(* Logix 5000 project; controller MVI56E_DNPNET 1756-L63 rev 16.7; software revision 16.04; part 2 of 2 *)
(* tags used below, declared in another part *)
   Connection_Output : INT[248];   // Output parameters.
   MJFAULTS : DINT[12];
(* AOI56EDNPNET, continued *)

ROUTINE Prescan   (* ladder *)
// Prescan
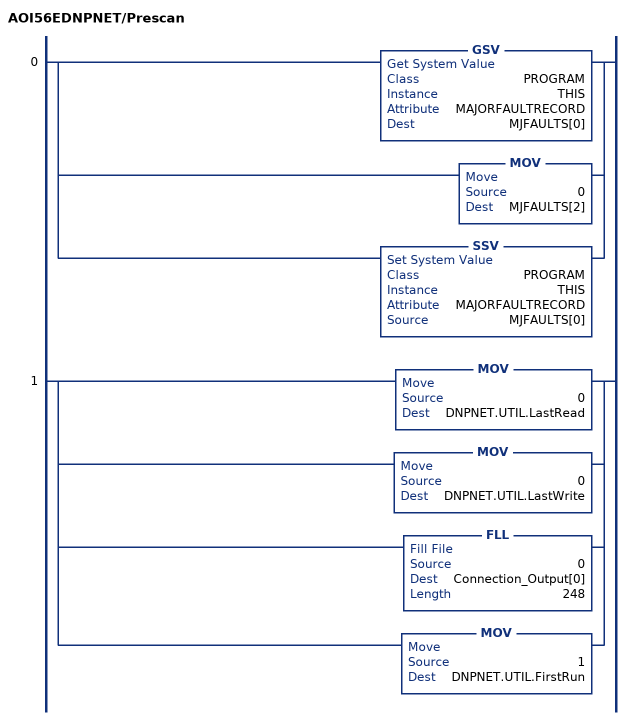
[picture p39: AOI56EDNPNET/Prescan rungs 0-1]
   0: [GSV(PROGRAM,THIS,MAJORFAULTRECORD,MJFAULTS[0]) ,MOV(0,MJFAULTS[2]) ,SSV(PROGRAM,THIS,MAJORFAULTRECORD,MJFAULTS[0]) ];
   1: [MOV(0,DNPNET.UTIL.LastRead) ,MOV(0,DNPNET.UTIL.LastWrite) ,FLL(0,Connection_Output[0],248) ,MOV(1,DNPNET.UTIL.FirstRun) ];
END_ROUTINE
END_ADD_ON_INSTRUCTION

VAR_GLOBAL   (* controller tags *)
   AOI56EDNPNET : AOI56EDNPNET;   // Add On Instruction for MVI56-DNPNET Module
   DNPNET : DNPNETMODULEDEF;
   ReadEthernetMSG : MESSAGE;   // Reads IP Adress from the Module
        MessageParameters(ServiceCode := 16#000e, DestinationTag := DNPNET.CONFIG.IP_Settings.IP, ...)
   WriteEthernetMSG : MESSAGE;   // Writes IP Addres to the Module
        MessageParameters(ServiceCode := 16#0010, LocalElement := DNPNET.CONFIG.IP_Settings.IP, ...)
END_VAR

PROGRAM MainProgram   (* main routine MainRoutine *)

ROUTINE MainRoutine   (* ladder *)
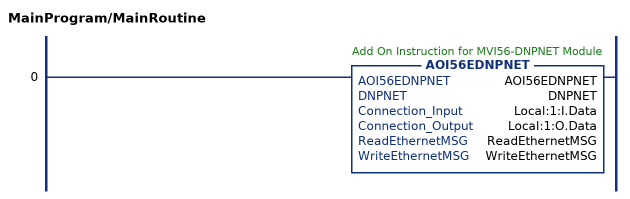
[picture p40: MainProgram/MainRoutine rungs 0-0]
   0: AOI56EDNPNET(AOI56EDNPNET,DNPNET,Local:1:I.Data,Local:1:O.Data,ReadEthernetMSG,WriteEthernetMSG);
END_ROUTINE
END_PROGRAM
